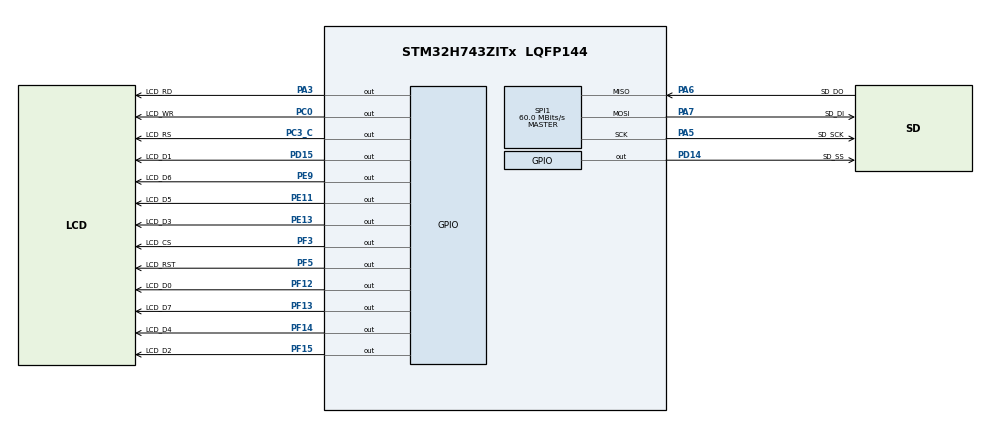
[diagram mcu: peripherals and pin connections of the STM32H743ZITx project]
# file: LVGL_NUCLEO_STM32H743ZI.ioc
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ADC3.Channel-0\#ChannelRegularConversion=ADC_CHANNEL_TEMPSENSOR
ADC3.NbrOfConversionFlag=1
ADC3.OffsetNumber-0\#ChannelRegularConversion=ADC_OFFSET_NONE
ADC3.OffsetSignedSaturation-0\#ChannelRegularConversion=DISABLE
ADC3.Rank-0\#ChannelRegularConversion=1
ADC3.SamplingTime-0\#ChannelRegularConversion=ADC_SAMPLETIME_1CYCLE_5
CORTEX_M7.default_mode_Activation=1
Mcu.Family=STM32H7
Mcu.Name=STM32H743ZITx
Mcu.Package=LQFP144
NUCLEO-H743ZI2.BUTTON=1
NUCLEO-H743ZI2.Bsp_Common_DEMO=true
NUCLEO-H743ZI2.LD1=true
NUCLEO-H743ZI2.LD2=true
NUCLEO-H743ZI2.LD3=true
NUCLEO-H743ZI2.VCP=true
NVIC.EXTI15_10_IRQn=true\:0\:0\:false\:false\:true\:false\:true\:true
NVIC.PriorityGroup=NVIC_PRIORITYGROUP_4
PA13\ (JTMS/SWDIO).GPIO_Label=JTMS
PA13\ (JTMS/SWDIO).Signal=DEBUG_JTMS-SWDIO
PA14\ (JTCK/SWCLK).GPIO_Label=JTCK
PA14\ (JTCK/SWCLK).Signal=DEBUG_JTCK-SWCLK
PA3.GPIO_Label=LCD_RD
PA3.Signal=GPIO_Output
PA5.GPIO_Label=SD_SCK
PA5.Mode=Full_Duplex_Master
PA5.Signal=SPI1_SCK
PA6.GPIO_Label=SD_DO
PA6.Mode=Full_Duplex_Master
PA6.Signal=SPI1_MISO
PA7.GPIO_Label=SD_DI
PA7.Mode=Full_Duplex_Master
PA7.Signal=SPI1_MOSI
PC0.GPIO_Label=LCD_WR
PC0.Signal=GPIO_Output
PC14-OSC32_IN\ (OSC32_IN).Signal=RCC_OSC32_IN
PC15-OSC32_OUT\ (OSC32_OUT).Signal=RCC_OSC32_OUT
PC3_C.GPIO_Label=LCD_RS
PC3_C.Signal=GPIO_Output
PD14.GPIO_Label=SD_SS
PD14.Signal=GPIO_Output
PD15.GPIO_Label=LCD_D1
PD15.Signal=GPIO_Output
PD8.Signal=USART3_TX
PD9.Signal=USART3_RX
PE11.GPIO_Label=LCD_D5
PE11.Signal=GPIO_Output
PE13.GPIO_Label=LCD_D3
PE13.Signal=GPIO_Output
PE9.GPIO_Label=LCD_D6
PE9.Signal=GPIO_Output
PF12.GPIO_Label=LCD_D0
PF12.Signal=GPIO_Output
PF13.GPIO_Label=LCD_D7
PF13.Signal=GPIO_Output
PF14.GPIO_Label=LCD_D4
PF14.Signal=GPIO_Output
PF15.GPIO_Label=LCD_D2
PF15.Signal=GPIO_Output
PF3.GPIO_Label=LCD_CS
PF3.Signal=GPIO_Output
PF5.GPIO_Label=LCD_RST
PF5.Signal=GPIO_Output
PH0-OSC_IN\ (PH0).Signal=RCC_OSC_IN
PH1-OSC_OUT\ (PH1).Signal=RCC_OSC_OUT
ProjectManager.HeapSize=0x200
ProjectManager.StackSize=0x400
ProjectManager.TargetToolchain=CMake
RCC.ADCFreq_Value=75000000
RCC.APB1Freq_Value=120000000
RCC.APB2Freq_Value=120000000
RCC.APB3Freq_Value=120000000
RCC.APB4Freq_Value=120000000
RCC.CortexFreq_Value=240000000
RCC.DIVM1=2
RCC.DIVN1=30
RCC.DIVN2=150
RCC.DIVN3=150
RCC.DIVQ1=4
RCC.HCLKFreq_Value=120000000
RCC.HPRE=RCC_HCLK_DIV2
RCC.HSIDiv=RCC_PLLSAIDIVR_2
RCC.PLLFRACN=0
RCC.SYSCLKFreq_VALUE=240000000
RCC.SYSCLKSource=RCC_SYSCLKSOURCE_PLLCLK
RCC.USBFreq_Value=120000000
SPI1.CalculateBaudRate=60.0 MBits/s
SPI1.Direction=SPI_DIRECTION_2LINES
SPI1.Mode=SPI_MODE_MASTER
SPI1.VirtualType=VM_MASTER
VP_ADC3_TempSens_Input.Mode=IN-TempSens
VP_ADC3_Vref_Input.Mode=IN-Vrefint
VP_MEMORYMAP_VS_MEMORYMAP.Mode=CurAppReg
VP_NUCLEO-H743ZI2_VS_BSP_COMMON.Mode=COMMON
board=NUCLEO-H743ZI2

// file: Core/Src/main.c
/* USER CODE BEGIN Header */
/**
  ******************************************************************************
  * @file           : main.c
  * @brief          : Main program body
  ******************************************************************************
  * @attention
  *
  * Copyright (c) 2026 STMicroelectronics.
  * All rights reserved.
  *
  * This software is licensed under terms that can be found in the LICENSE file
  * in the root directory of this software component.
  * If no LICENSE file comes with this software, it is provided AS-IS.
  *
  ******************************************************************************
  */
/* USER CODE END Header */
#include "main.h"
#include "adc.h"
#include "spi.h"
#include "gpio.h"

COM_InitTypeDef BspCOMInit;
__IO uint32_t BspButtonState = BUTTON_RELEASED;

void SystemClock_Config(void);
static void MPU_Config(void);
/* USER CODE BEGIN PFP */
extern void InitializeLvgl();
extern void LoadLvglScreen();
extern void UpdateLvglScreen();
/* USER CODE END PFP */

int main(void)
{

  /* MPU Configuration--------------------------------------------------------*/
  MPU_Config();

  /* MCU Configuration--------------------------------------------------------*/

  /* Reset of all peripherals, Initializes the Flash interface and the Systick. */
  HAL_Init();

  /* Configure the system clock */
  SystemClock_Config();

  /* Initialize all configured peripherals */
  MX_GPIO_Init();
  MX_SPI1_Init();
  MX_ADC3_Init();

  /* Initialize leds */
  BSP_LED_Init(LED_GREEN);
  BSP_LED_Init(LED_YELLOW);
  BSP_LED_Init(LED_RED);

  /* Initialize USER push-button, will be used to trigger an interrupt each time it's pressed.*/
  BSP_PB_Init(BUTTON_USER, BUTTON_MODE_EXTI);

  /* Initialize COM1 port (115200, 8 bits (7-bit data + 1 stop bit), no parity */
  BspCOMInit.BaudRate   = 115200;
  BspCOMInit.WordLength = COM_WORDLENGTH_8B;
  BspCOMInit.StopBits   = COM_STOPBITS_1;
  BspCOMInit.Parity     = COM_PARITY_NONE;
  BspCOMInit.HwFlowCtl  = COM_HWCONTROL_NONE;
  if (BSP_COM_Init(COM1, &BspCOMInit) != BSP_ERROR_NONE)
  {
    Error_Handler();
  }

  /* USER CODE BEGIN BSP */

  /* -- Sample board code to send message over COM1 port ---- */
  printf("Welcome to STM32 world !\n\r");

  /* -- Sample board code to switch on leds ---- */
  BSP_LED_On(LED_GREEN);
  BSP_LED_On(LED_YELLOW);
  BSP_LED_On(LED_RED);

  InitializeLvgl();
  LoadLvglScreen();
  /* USER CODE END BSP */

  /* Infinite loop */
  /* USER CODE BEGIN WHILE */
  while (1)
  {

    /* -- Sample board code for User push-button in interrupt mode ---- */
    if (BspButtonState == BUTTON_PRESSED)
    {
      /* Update button state */
      BspButtonState = BUTTON_RELEASED;
      /* -- Sample board code to toggle leds ---- */
      BSP_LED_Toggle(LED_GREEN);
      BSP_LED_Toggle(LED_YELLOW);
      BSP_LED_Toggle(LED_RED);

      /* ..... Perform your action ..... */
    }
    /* USER CODE END WHILE */

    /* USER CODE BEGIN 3 */
    UpdateLvglScreen();
  }
  /* USER CODE END 3 */
}

void SystemClock_Config(void)
{
  RCC_OscInitTypeDef RCC_OscInitStruct = {0};
  RCC_ClkInitTypeDef RCC_ClkInitStruct = {0};

  /** Supply configuration update enable
  */
  HAL_PWREx_ConfigSupply(PWR_LDO_SUPPLY);

  /** Configure the main internal regulator output voltage
  */
  __HAL_PWR_VOLTAGESCALING_CONFIG(PWR_REGULATOR_VOLTAGE_SCALE0);

  while(!__HAL_PWR_GET_FLAG(PWR_FLAG_VOSRDY)) {}

  /** Initializes the RCC Oscillators according to the specified parameters
  * in the RCC_OscInitTypeDef structure.
  */
  RCC_OscInitStruct.OscillatorType = RCC_OSCILLATORTYPE_HSI;
  RCC_OscInitStruct.HSIState = RCC_HSI_DIV2;
  RCC_OscInitStruct.HSICalibrationValue = RCC_HSICALIBRATION_DEFAULT;
  RCC_OscInitStruct.PLL.PLLState = RCC_PLL_ON;
  RCC_OscInitStruct.PLL.PLLSource = RCC_PLLSOURCE_HSI;
  RCC_OscInitStruct.PLL.PLLM = 2;
  RCC_OscInitStruct.PLL.PLLN = 30;
  RCC_OscInitStruct.PLL.PLLP = 2;
  RCC_OscInitStruct.PLL.PLLQ = 4;
  RCC_OscInitStruct.PLL.PLLR = 2;
  RCC_OscInitStruct.PLL.PLLRGE = RCC_PLL1VCIRANGE_3;
  RCC_OscInitStruct.PLL.PLLVCOSEL = RCC_PLL1VCOWIDE;
  RCC_OscInitStruct.PLL.PLLFRACN = 0;
  if (HAL_RCC_OscConfig(&RCC_OscInitStruct) != HAL_OK)
  {
    Error_Handler();
  }

  /** Initializes the CPU, AHB and APB buses clocks
  */
  RCC_ClkInitStruct.ClockType = RCC_CLOCKTYPE_HCLK|RCC_CLOCKTYPE_SYSCLK
                              |RCC_CLOCKTYPE_PCLK1|RCC_CLOCKTYPE_PCLK2
                              |RCC_CLOCKTYPE_D3PCLK1|RCC_CLOCKTYPE_D1PCLK1;
  RCC_ClkInitStruct.SYSCLKSource = RCC_SYSCLKSOURCE_PLLCLK;
  RCC_ClkInitStruct.SYSCLKDivider = RCC_SYSCLK_DIV1;
  RCC_ClkInitStruct.AHBCLKDivider = RCC_HCLK_DIV2;
  RCC_ClkInitStruct.APB3CLKDivider = RCC_APB3_DIV1;
  RCC_ClkInitStruct.APB1CLKDivider = RCC_APB1_DIV1;
  RCC_ClkInitStruct.APB2CLKDivider = RCC_APB2_DIV1;
  RCC_ClkInitStruct.APB4CLKDivider = RCC_APB4_DIV1;

  if (HAL_RCC_ClockConfig(&RCC_ClkInitStruct, FLASH_LATENCY_1) != HAL_OK)
  {
    Error_Handler();
  }
}

 /* MPU Configuration */

void MPU_Config(void)
{
  MPU_Region_InitTypeDef MPU_InitStruct = {0};

  /* Disables the MPU */
  HAL_MPU_Disable();

  /** Initializes and configures the Region and the memory to be protected
  */
  MPU_InitStruct.Enable = MPU_REGION_ENABLE;
  MPU_InitStruct.Number = MPU_REGION_NUMBER0;
  MPU_InitStruct.BaseAddress = 0x0;
  MPU_InitStruct.Size = MPU_REGION_SIZE_4GB;
  MPU_InitStruct.SubRegionDisable = 0x87;
  MPU_InitStruct.TypeExtField = MPU_TEX_LEVEL0;
  MPU_InitStruct.AccessPermission = MPU_REGION_NO_ACCESS;
  MPU_InitStruct.DisableExec = MPU_INSTRUCTION_ACCESS_DISABLE;
  MPU_InitStruct.IsShareable = MPU_ACCESS_SHAREABLE;
  MPU_InitStruct.IsCacheable = MPU_ACCESS_NOT_CACHEABLE;
  MPU_InitStruct.IsBufferable = MPU_ACCESS_NOT_BUFFERABLE;

  HAL_MPU_ConfigRegion(&MPU_InitStruct);
  /* Enables the MPU */
  HAL_MPU_Enable(MPU_PRIVILEGED_DEFAULT);

}

/**
  * @brief BSP Push Button callback
  * @param Button Specifies the pressed button
  * @retval None
  */
void BSP_PB_Callback(Button_TypeDef Button)
{
  if (Button == BUTTON_USER)
  {
    BspButtonState = BUTTON_PRESSED;
  }
}

void Error_Handler(void)
{
  __disable_irq();
  while (1)
  {
  }
}
